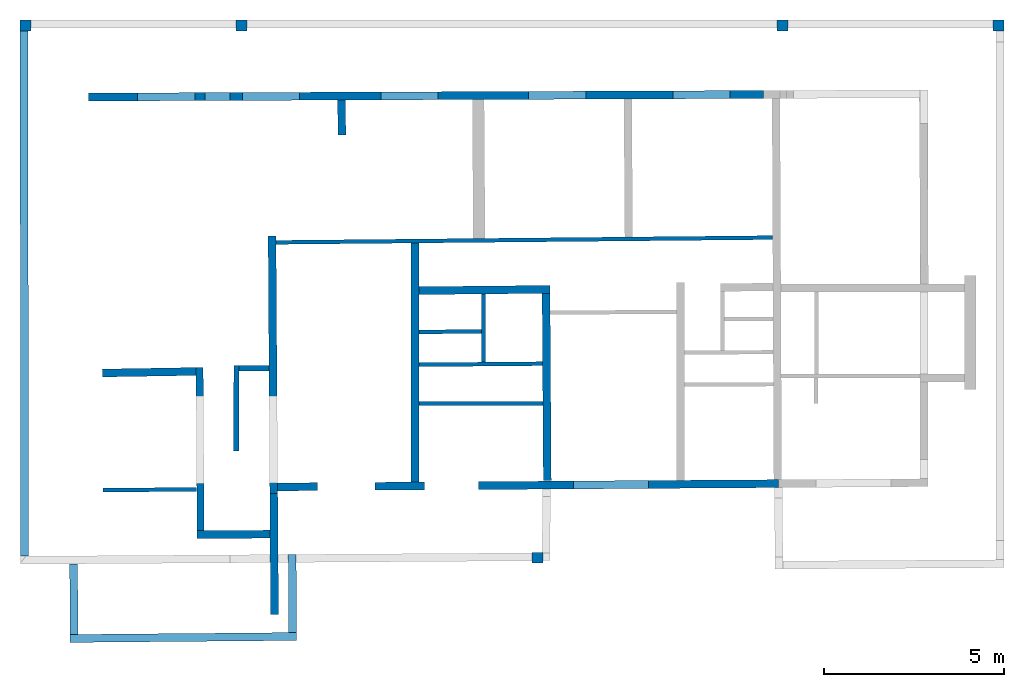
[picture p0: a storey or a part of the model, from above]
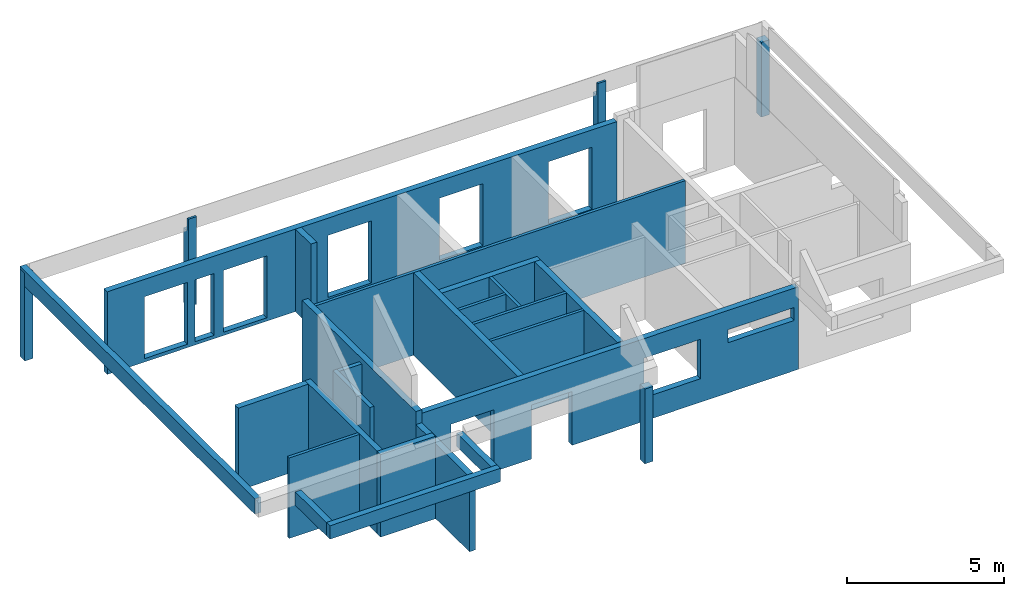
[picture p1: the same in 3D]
Properties of the parts of a building model (IFC2X3)

# File
Description: ViewDefinition [CoordinationView_V2.0], RevitIdentifiers [ContentGUID: feac69e5-6f6e-46f0-a33a-da2cc0dcfcfa, VersionGUID: e0802a1b-6d15-4124-863f-2c3c3ba81dfb, NumberOfSaves: 98], CoordinateReference [CoordinateBase: Origine interne, ProjectSite: Site par défaut]
File name: F3_26_978_MAQUETTE STRUCTURE_REFECTION TOITURE ONF_IFC IND 0_300926.ifc
Time: 2026-09-30T17:36:53+04:00
Author: Samuel Bello, s.bello@darwin-concept.fr
Organization: EICR
Written by: ODA SDAI 25.12
Made in: Autodesk Revit 26.2.0.20 (FRA) - IFC 26.2.0.20

# IfcProject, 09072019
LongName: SIDR_BAG; Phase: Etat du projet

# IfcSite, Default
RefLatitude: 42, 24, 53, 508911; RefLongitude: -71, -15, -29, -58837; RefElevation: 13090 cm

# IfcBuilding, e 39 logements et 22 maisons relais
LongName: e 39 logements et 22 maisons relais
Pset_BuildingCommon - NumberOfStoreys: 9

# IfcBuildingStorey: Niveau:Niveau NGR (3)
In: e 39 logements et 22 maisons relais
Name | LongName | Elevation (cm)
niv 0.00 | niv 0.00 | -13160
131.04 | 131.04 | 14
faîtage | faîtage | 825

# IfcBuildingStorey: Niveau:Niveau Relatif + NGR (6)
In: e 39 logements et 22 maisons relais
Name | LongName | Elevation (cm)
Fondations | Fondations | -410
Parking | Parking | -330
RDC | RDC | 0
R+1 | R+1 | 340
R+2 | R+2 | 610
R+3 | R+3 | 810

# IfcBeam: Poutre - Bois de construction de dimensions courantes:50 50 (239)
Type - PredefinedType: BEAM
Type - Pset_BeamCommon - LoadBearing: yes
Material: Bois - Bois de construction de dimensions courantes
Pset_BeamCommon - IsExternal: no; Reference: 50 50
Pset_QuantityTakeOff - Reference: 50 50; sets with these values: 2
Name (Poutre - Bois de construction de dimensions courantes:50 50:...) | In | Span (cm) | Slope (deg)
4829898 | R+2 | 364.7 | 19.8244
4829899 | R+2 | 364.7 | 36.3275
4829900 | R+2 | 364.7 | 36.933
4829901 | R+2 | 364.7 | 20.2495
4831531 | R+3 | 8.2 | 34.9359
4840642 | R+2 | 364.7 | 36.3605
4843238 | R+2 | 350.3 | 41.8622
4846561 | R+2 | 8.2 | 35.1202
4846562 | R+2 | 364.7 | 38.3386
4846563 | R+2 | 8.2 | 35.8385
4846564 | R+2 | 364.7 | 34.959
4851425 | R+2 | 350.3 | 41.9439
4883018 | R+2 | 364.7 | 19.8244 | Group: Groupe de modèles:Groupe 5:4883022
4883019 | R+2 | 364.7 | 36.3275 | Group: Groupe de modèles:Groupe 5:4883022
4883020 | R+2 | 364.7 | 36.933 | Group: Groupe de modèles:Groupe 5:4883022
4883021 | R+2 | 364.7 | 20.2495 | Group: Groupe de modèles:Groupe 5:4883022
4883032 | R+2 | 364.7 | 19.8244 | Group: Groupe de modèles:Groupe 5:4883036
4883033 | R+2 | 364.7 | 36.3275 | Group: Groupe de modèles:Groupe 5:4883036
4883034 | R+2 | 364.7 | 36.933 | Group: Groupe de modèles:Groupe 5:4883036
4883035 | R+2 | 364.7 | 20.2495 | Group: Groupe de modèles:Groupe 5:4883036
4883050 | R+2 | 364.7 | 19.8244 | Group: Groupe de modèles:Groupe 5:4883054
4883051 | R+2 | 364.7 | 36.3275 | Group: Groupe de modèles:Groupe 5:4883054
4883052 | R+2 | 364.7 | 36.933 | Group: Groupe de modèles:Groupe 5:4883054
4883053 | R+2 | 364.7 | 20.2495 | Group: Groupe de modèles:Groupe 5:4883054
4883089 | R+2 | 364.7 | 19.8244 | Group: Groupe de modèles:Groupe 5:4883093
4883090 | R+2 | 364.7 | 36.3275 | Group: Groupe de modèles:Groupe 5:4883093
4883091 | R+2 | 364.7 | 36.933 | Group: Groupe de modèles:Groupe 5:4883093
4883092 | R+2 | 364.7 | 20.2495 | Group: Groupe de modèles:Groupe 5:4883093
4883094 | R+2 | 364.7 | 19.8244 | Group: Groupe de modèles:Groupe 5:4883098
4883095 | R+2 | 364.7 | 36.3275 | Group: Groupe de modèles:Groupe 5:4883098
4883096 | R+2 | 364.7 | 36.933 | Group: Groupe de modèles:Groupe 5:4883098
4883097 | R+2 | 364.7 | 20.2495 | Group: Groupe de modèles:Groupe 5:4883098
4883099 | R+2 | 364.7 | 19.8244
4883100 | R+2 | 364.7 | 36.3275
4883101 | R+2 | 364.7 | 36.933
4883102 | R+2 | 364.7 | 20.2495
4883146 | R+2 | 364.7 | 19.6626
4883147 | R+2 | 364.7 | 36.6815
4883148 | R+2 | 364.7 | 36.382
4883149 | R+2 | 364.7 | 20.4762
4883202 | R+2 | 364.7 | 19.8244
4883203 | R+2 | 364.7 | 36.3275
4883204 | R+2 | 364.7 | 36.933
4883205 | R+2 | 364.7 | 20.2495
4883212 | R+2 | 364.7 | 19.8244
4883213 | R+2 | 364.7 | 36.3275
4883214 | R+2 | 364.7 | 36.933
4883215 | R+2 | 364.7 | 20.2495
4883217 | R+2 | 364.7 | 19.8244
4883218 | R+2 | 364.7 | 36.3275
4883219 | R+2 | 364.7 | 36.933
4883220 | R+2 | 364.7 | 20.2495
4883222 | R+2 | 364.7 | 19.8244
4883223 | R+2 | 364.7 | 36.3275
4883224 | R+2 | 364.7 | 36.933
4883225 | R+2 | 364.7 | 20.2495
4883239 | R+2 | 364.7 | 19.8244 | Group: Groupe de modèles:Groupe 5:4883243
4883240 | R+2 | 364.7 | 36.3275 | Group: Groupe de modèles:Groupe 5:4883243
4883241 | R+2 | 364.7 | 36.933 | Group: Groupe de modèles:Groupe 5:4883243
4883242 | R+2 | 364.7 | 20.2495 | Group: Groupe de modèles:Groupe 5:4883243
4883244 | R+2 | 364.7 | 19.8244 | Group: Groupe de modèles:Groupe 5:4883248
4883245 | R+2 | 364.7 | 36.3275 | Group: Groupe de modèles:Groupe 5:4883248
4883246 | R+2 | 364.7 | 36.933 | Group: Groupe de modèles:Groupe 5:4883248
4883247 | R+2 | 364.7 | 20.2495 | Group: Groupe de modèles:Groupe 5:4883248
4883249 | R+2 | 364.7 | 19.8244 | Group: Groupe de modèles:Groupe 5:4883253
4883250 | R+2 | 364.7 | 36.3275 | Group: Groupe de modèles:Groupe 5:4883253
4883251 | R+2 | 364.7 | 36.933 | Group: Groupe de modèles:Groupe 5:4883253
4883252 | R+2 | 364.7 | 20.2495 | Group: Groupe de modèles:Groupe 5:4883253
4883254 | R+2 | 364.7 | 19.8244 | Group: Groupe de modèles:Groupe 5:4883258
4883255 | R+2 | 364.7 | 36.3275 | Group: Groupe de modèles:Groupe 5:4883258
4883256 | R+2 | 364.7 | 36.933 | Group: Groupe de modèles:Groupe 5:4883258
4883257 | R+2 | 364.7 | 20.2495 | Group: Groupe de modèles:Groupe 5:4883258
4883259 | R+2 | 364.7 | 19.8244
4883260 | R+2 | 364.7 | 36.3275
4883261 | R+2 | 364.7 | 36.933
4883262 | R+2 | 364.7 | 20.2495
4883275 | R+2 | 364.7 | 19.8244 | Group: Groupe de modèles:Groupe 5:4883279
4883276 | R+2 | 364.7 | 36.3275 | Group: Groupe de modèles:Groupe 5:4883279
4883277 | R+2 | 364.7 | 36.933 | Group: Groupe de modèles:Groupe 5:4883279
4883278 | R+2 | 364.7 | 20.2495 | Group: Groupe de modèles:Groupe 5:4883279
4883280 | R+2 | 364.7 | 19.8244 | Group: Groupe de modèles:Groupe 5:4883284
4883281 | R+2 | 364.7 | 36.3275 | Group: Groupe de modèles:Groupe 5:4883284
4883282 | R+2 | 364.7 | 36.933 | Group: Groupe de modèles:Groupe 5:4883284
4883283 | R+2 | 364.7 | 20.2495 | Group: Groupe de modèles:Groupe 5:4883284
4883285 | R+2 | 364.7 | 19.8244 | Group: Groupe de modèles:Groupe 5:4883289
4883286 | R+2 | 364.7 | 36.3275 | Group: Groupe de modèles:Groupe 5:4883289
4883287 | R+2 | 364.7 | 36.933 | Group: Groupe de modèles:Groupe 5:4883289
4883288 | R+2 | 364.7 | 20.2495 | Group: Groupe de modèles:Groupe 5:4883289
4883290 | R+2 | 364.7 | 19.8244 | Group: Groupe de modèles:Groupe 5:4883294
4883291 | R+2 | 364.7 | 36.3275 | Group: Groupe de modèles:Groupe 5:4883294
4883292 | R+2 | 364.7 | 36.933 | Group: Groupe de modèles:Groupe 5:4883294
4883293 | R+2 | 364.7 | 20.2495 | Group: Groupe de modèles:Groupe 5:4883294
4883295 | R+2 | 364.7 | 19.8244 | Group: Groupe de modèles:Groupe 5:4883299
4883296 | R+2 | 364.7 | 36.3275 | Group: Groupe de modèles:Groupe 5:4883299
4883297 | R+2 | 364.7 | 36.933 | Group: Groupe de modèles:Groupe 5:4883299
4883298 | R+2 | 364.7 | 20.2495 | Group: Groupe de modèles:Groupe 5:4883299
4883331 | R+2 | 364.7 | 20.1552
4883332 | R+2 | 364.7 | 35.4788
4883333 | R+2 | 364.7 | 38.2563
4883334 | R+2 | 364.7 | 19.6937
4883336 | R+2 | 364.7 | 19.8244 | Group: Groupe de modèles:Groupe 5:4883340
4883337 | R+2 | 364.7 | 36.3275 | Group: Groupe de modèles:Groupe 5:4883340
4883338 | R+2 | 364.7 | 36.933 | Group: Groupe de modèles:Groupe 5:4883340
4883339 | R+2 | 364.7 | 20.2495 | Group: Groupe de modèles:Groupe 5:4883340
4883432 | R+2 | 364.7 | 19.8244
4883433 | R+2 | 364.7 | 36.3275
4883434 | R+2 | 364.7 | 36.933
4883435 | R+2 | 364.7 | 20.2495
4883478 | R+2 | 364.7 | 19.8244
4883479 | R+2 | 364.7 | 36.3275
4883480 | R+2 | 364.7 | 36.933
4883481 | R+2 | 364.7 | 20.2495
4883519 | R+2 | 364.7 | 19.8244
4883520 | R+2 | 364.7 | 36.3275
4883521 | R+2 | 364.7 | 36.933
4883522 | R+2 | 364.7 | 20.2495
4883581 | R+2 | 364.7 | 19.8244 | Group: Groupe de modèles:Groupe 5:4883585
4883582 | R+2 | 364.7 | 36.3275 | Group: Groupe de modèles:Groupe 5:4883585
4883583 | R+2 | 364.7 | 36.933 | Group: Groupe de modèles:Groupe 5:4883585
4883584 | R+2 | 364.7 | 20.2495 | Group: Groupe de modèles:Groupe 5:4883585
4901794 | R+2 | 364.7 | 35.9094
4907943 | R+3 | 8.2 | 34.9359
4907953 | R+3 | 8.2 | 34.9359
4907959 | R+3 | 8.2 | 34.9359
4907969 | R+3 | 8.2 | 34.9359
4908079 | R+3 | 8.2 | 34.9359
4908080 | R+3 | 8.2 | 35.9359
4908081 | R+3 | 8.2 | 34.9359
4908082 | R+3 | 8.2 | 34.9359
4908092 | R+3 | 8.2 | 34.9359
4908093 | R+3 | 8.2 | 34.9359
4908094 | R+3 | 8.2 | 34.9359
4908095 | R+3 | 8.2 | 34.9359
4908107 | R+3 | 8.2 | 35.9094
4915457 | R+2 | 364.7 | 35.9094
4915467 | R+2 | 364.7 | 35.9094
4915475 | R+2 | 364.7 | 35.9094
4915487 | R+2 | 364.7 | 35.9094
4915495 | R+2 | 364.7 | 35.9094
4915505 | R+2 | 364.7 | 35.9094
4915567 | R+2 | 364.7 | 35.9094
4916020 | R+2 | 8.2 | 35.4828
4916028 | R+2 | 8.2 | 35.4828
4916038 | R+2 | 8.2 | 35.4828
4916048 | R+2 | 8.2 | 35.4828
4916054 | R+2 | 8.2 | 35.4828
4916062 | R+2 | 8.2 | 35.4828
4916070 | R+2 | 8.2 | 35.4828
4916082 | R+2 | 8.2 | 35.4828
4932576 | R+2 | 8.2 | 35.4828
4932582 | R+2 | 8.2 | 35.4828
4932650 | R+2 | 8.2 | 35.4828
4932658 | R+2 | 8.2 | 35.4828
4932668 | R+2 | 8.2 | 35.4828
4932794 | R+2 | 8.2 | 35.4828
4932795 | R+2 | 8.2 | 35.4828
4932796 | R+2 | 8.2 | 35.4828
4932797 | R+2 | 8.2 | 35.4828
4932809 | R+2 | 8.2 | 35.4828
4932810 | R+2 | 8.2 | 35.4828
4932811 | R+2 | 8.2 | 35.4828
4932812 | R+2 | 8.2 | 35.4828
4932822 | R+2 | 8.2 | 35.4828
4932823 | R+2 | 8.2 | 35.4828
4932824 | R+2 | 8.2 | 35.4828
4932825 | R+2 | 8.2 | 35.4828
4932867 | R+2 | 8.2 | 35.4828
4932948 | R+2 | 8.2 | 35.4828
4932949 | R+2 | 8.2 | 35.4828
4932950 | R+2 | 8.2 | 35.4828
4932951 | R+2 | 8.2 | 35.4828
4932960 | R+2 | 8.2 | 35.4828
4932961 | R+2 | 8.2 | 35.4828
4932962 | R+2 | 8.2 | 35.4828
4946928 | R+2 | 350.3 | 41.8805
4946974 | R+2 | 350.3 | 41.8805
4947018 | R+2 | 350.3 | 41.8805
4947064 | R+2 | 350.3 | 41.8805
4947108 | R+2 | 350.3 | 41.8805
4947152 | R+2 | 350.3 | 41.8805
4947282 | R+2 | 350.3 | 41.8805
4947328 | R+2 | 350.3 | 41.8805
4947372 | R+2 | 350.3 | 41.8805
4947416 | R+2 | 350.3 | 41.8805
4948711 | R+2 | 350.3 | 41.9439
4949085 | R+2 | 350.3 | 41.9439
4949111 | R+2 | 350.3 | 41.9439
4949197 | R+2 | 350.3 | 41.8805
4949349 | R+2 | 350.3 | 41.8805
4949357 | R+2 | 350.3 | 41.8805
4949367 | R+2 | 350.3 | 41.8805
4949375 | R+2 | 350.3 | 41.8805
4949383 | R+2 | 350.3 | 41.8805
4949395 | R+2 | 350.3 | 41.8805
4949405 | R+2 | 350.3 | 41.8805
4949415 | R+2 | 350.3 | 41.8805
4949423 | R+2 | 350.3 | 41.8805
4951378 | R+2 | 8.2 | 35.1202
4951380 | R+2 | 8.2 | 35.8385
4951502 | R+2 | 8.2 | 35.1202
4951503 | R+2 | 8.2 | 35.8385
4951513 | R+2 | 8.2 | 35.1202
4951514 | R+2 | 8.2 | 35.8385
4951526 | R+2 | 8.2 | 35.1202
4951527 | R+2 | 8.2 | 35.8385
4951561 | R+2 | 8.2 | 35.1202
4951562 | R+2 | 8.2 | 35.8385
4952038 | R+2 | 8.2 | 35.8385
4952046 | R+2 | 8.2 | 35.8385
4952054 | R+2 | 8.2 | 35.8385
4960730 | R+2 | 350.3 | 41.8622
4960776 | R+2 | 350.3 | 41.8622
4960863 | R+2 | 350.3 | 41.8622
4960907 | R+2 | 350.3 | 41.8622
4960951 | R+2 | 350.3 | 41.8622
4960995 | R+2 | 350.3 | 41.8622
4961039 | R+2 | 350.3 | 41.8622
4961083 | R+2 | 350.3 | 41.8622
4961127 | R+2 | 350.3 | 41.8622
4961171 | R+2 | 350.3 | 41.8622
4961721 | R+2 | 350.3 | 41.8622
4961820 | R+2 | 350.3 | 41.8622
4961864 | R+2 | 350.3 | 41.8622
4961910 | R+2 | 350.3 | 41.8622
4961954 | R+2 | 350.3 | 41.8622
4961998 | R+2 | 350.3 | 41.8622
4962042 | R+2 | 350.3 | 41.8622
4962086 | R+2 | 350.3 | 41.8622
4962130 | R+2 | 350.3 | 41.8622
4962176 | R+2 | 350.3 | 41.8622
4962220 | R+2 | 350.3 | 41.8622
4970020 | R+2 | 8.2 | 35.4828
5042469 | R+2 | 8.2 | 35.1202
5042470 | R+2 | 364.7 | 38.3386
5042471 | R+2 | 8.2 | 35.8385
5042472 | R+2 | 364.7 | 34.959
5093514 | R+2 | 8.2 | 35.1202
5093524 | R+2 | 8.2 | 35.1202
5093532 | R+2 | 8.2 | 35.1202

# IfcBeam: Poutre - Bois de construction de dimensions courantes:70 100 (6)
Type - PredefinedType: BEAM
Type - Pset_BeamCommon - LoadBearing: yes
Material: Bois - Bois de construction de dimensions courantes
Pset_BeamCommon - IsExternal: no; Reference: 70 100
Pset_QuantityTakeOff - Reference: 70 100; sets with these values: 2
Name (Poutre - Bois de construction de dimensions courantes:70 100:...) | In | Span (cm) | Slope (deg)
4772331 | R+2 | 244.1 | 25.7882
4774475 | R+2 | 241.3 | 25.9653
4852667 | R+2 | 262.2 | 0
4853331 | R+3 | 262.2 | 0
4853339 | R+2 | 262.2 | 0
4853347 | R+2 | 262.2 | 0

# IfcBeam: Poutre - Bois de construction de dimensions courantes:70 200 (131)
Type - PredefinedType: BEAM
Type - Pset_BeamCommon - LoadBearing: yes
Material: Bois - Bois de construction de dimensions courantes
Pset_BeamCommon - IsExternal: no; Reference: 70 200
Pset_QuantityTakeOff - Reference: 70 200; sets with these values: 2
Name (Poutre - Bois de construction de dimensions courantes:70 200:...) | In | Span (cm) | Slope (deg)
4713617 | R+2 | 364.4 | 19.6829
4713659 | R+2 | 363.8 | 20.4762
4713696 | R+2 | 350.3 | 35.528
4713697 | R+2 | 364 | 35.7207
4713698 | R+1 | 221.5 | 0
4716714 | R+2 | 363.8 | 55.6387
4718998 | R+2 | 363.7 | 35.7207
4718999 | R+1 | 221.5 | 0
4720476 | faîtage | 221.5 | 0.151927
4720530 | faîtage | 221.5 | 0.0214582
4721840 | R+2 | 363.8 | 55.6387
4723570 | R+2 | 221.5 | 0
4724354 | R+2 | 221.5 | 0
4724410 | R+2 | 221.5 | 0
4724453 | R+2 | 221.5 | 0
4724504 | R+2 | 221.5 | 0
4724538 | R+3 | 221.5 | 0
4724595 | R+3 | 221.5 | 0
4725042 | R+3 | 221.5 | 0.201763
4725400 | faîtage | 221.5 | 0.141841
4725401 | faîtage | 221.5 | 0.0499903
4725402 | R+2 | 221.5 | 0
4725403 | R+2 | 221.5 | 0
4725404 | R+2 | 221.5 | 0
4725405 | R+2 | 221.5 | 0
4725406 | R+2 | 221.5 | 0
4725407 | R+3 | 221.5 | 0
4725408 | R+3 | 221.5 | 0
4725409 | R+3 | 221.5 | 0.239078
4727165 | R+1 | 221.5 | 0
4727559 | R+2 | 350.3 | 41.9619
4729826 | R+2 | 349.3 | 35.528
4730399 | R+2 | 364.4 | 20
4730420 | R+2 | 363.2 | 20.1834
4730442 | R+2 | 350.3 | 37.8496
4730443 | R+2 | 363.4 | 38
4730444 | R+2 | 221.5 | 0
4730466 | R+1 | 221.2 | 53.2663
4730481 | R+2 | 363.8 | 55.6387
4730534 | R+2 | 367.7 | 38
4730535 | R+2 | 221.5 | 0
4730550 | R+1 | 219.9 | 53.2663
4730619 | R+2 | 363.8 | 55.6387
4730755 | R+2 | 355.1 | 37.8496
4731622 | R+2 | 350.3 | 66.5157
4732101 | R+1 | 221.5 | 44
4732861 | R+1 | 221.5 | 0
4732862 | R+2 | 350.3 | 41.9619
4732876 | R+2 | 350.3 | 66.5157
4733129 | R+1 | 221.5 | 53
4733130 | R+1 | 221.5 | 0
4733131 | R+2 | 350.3 | 29.3869
4733145 | R+2 | 350.3 | 52.6147
4735480 | R+1 | 221.5 | 0
4735481 | R+2 | 351.2 | 29.3869
4735495 | R+2 | 350.3 | 52.6147
4735910 | R+2 | 350.3 | 41.9619
4737384 | R+2 | 350.3 | 41.9619
4738993 | R+2 | 113.9 | 29.3869
4739526 | R+2 | 113.9 | 29.3869
4739680 | R+2 | 113.9 | 29.3869
4739693 | R+2 | 113.9 | 29.3869
4744478 | R+1 | 221.5 | 0.0305164
4744486 | R+1 | 221.5 | 0.0283479
4744536 | R+1 | 221.5 | 0.0105581
4744757 | R+2 | 221.5 | 30.4756
4745406 | R+2 | 221.5 | 30.4756
4745808 | R+1 | 110.1 | 0.185532
4746326 | R+1 | 202.2 | 0
4746422 | R+1 | 214.2 | 0.359982
4746951 | R+2 | 113.4 | 35.1814
4750679 | R+1 | 221.5 | 53
4750680 | R+1 | 221.5 | 0
4750681 | R+2 | 350.3 | 29.3869
4750695 | R+2 | 354.9 | 51.6489
4750729 | R+1 | 221.5 | 0
4750730 | R+2 | 351.2 | 29.3869
4750744 | R+2 | 350.3 | 52.6147
4754543 | faîtage | 221.5 | 0
4754544 | R+2 | 221.5 | 0
4754545 | R+2 | 221.5 | 0
4754546 | R+2 | 221.5 | 0
4754547 | R+3 | 221.5 | 0
4754548 | R+3 | 221.5 | 0
4754549 | R+2 | 221.5 | 0
4754550 | R+1 | 221.5 | 0
4754551 | R+1 | 221.5 | 0
4754552 | R+1 | 221.5 | 0
4756969 | R+1 | 221.5 | 53
4756970 | R+1 | 221.5 | 0
4756971 | R+2 | 350.3 | 29.3869
4756985 | R+2 | 354.9 | 51.6489
4757006 | R+1 | 221.5 | 0
4757007 | R+2 | 351.2 | 29.3869
4757021 | R+2 | 350.3 | 52.6147
4757707 | R+1 | 221.5 | 0
4757708 | R+2 | 350.3 | 41.8805
4757722 | R+2 | 350.3 | 71.3198
4757723 | R+1 | 185.2 | 30.6789
4757787 | R+1 | 221.5 | 0
4757788 | R+2 | 350.3 | 41.8805
4757802 | R+2 | 350.3 | 71.3198
4758155 | R+1 | 221.5 | 0
4758156 | R+2 | 350.3 | 29.3869
4758170 | R+2 | 354.9 | 51.6489
4758184 | R+1 | 221.5 | 0
4758185 | R+2 | 351.2 | 29.3869
4759985 | R+2 | 363.8 | 20.3198
4760008 | R+2 | 221.5 | 0
4760055 | R+2 | 363.7 | 35.9222
4760056 | R+2 | 221.5 | 0
4771403 | R+2 | 330.7 | 52.6147
4814569 | R+3 | 221.5 | 0.173631
4814640 | R+2 | 221.5 | 0.044149
4814849 | R+3 | 221.5 | 0.149923
4814945 | R+3 | 221.5 | 0.113566
4814953 | R+2 | 221.5 | 0.0922914
4814961 | R+2 | 221.5 | 0.071892
4817865 | R+2 | 221.5 | 0.056568
4818210 | R+3 | 221.5 | 0.265412
4818318 | R+3 | 221.5 | 0.22199
4818326 | R+3 | 221.5 | 0.195658
4818334 | R+2 | 221.5 | 0.140445
4818342 | R+2 | 221.5 | 0.107412
4822862 | R+2 | 221.5 | 0
4825191 | R+1 | 221.5 | 0
4861459 | R+1 | 110.1 | 0
4908987 | R+1 | 8.2 | 35.9359
4959918 | R+1 | 221.5 | 0
5052351 | R+1 | 221.5 | 0
5077321 | R+2 | 221.5 | 0

# IfcBeam: Poutre - Bois de construction de dimensions courantes:70 220 (62)
Type - PredefinedType: BEAM
Type - Pset_BeamCommon - LoadBearing: yes
Material: Bois - Bois de construction de dimensions courantes
Pset_BeamCommon - IsExternal: no; Reference: 70 220
Pset_QuantityTakeOff - Reference: 70 220; sets with these values: 2
Name (Poutre - Bois de construction de dimensions courantes:70 220:...) | In | Span (cm) | Slope (deg)
4713592 | R+1 | 237.6 | 14.6236
4713594 | R+3 | 221.5 | 90
4713595 | R+2 | 221.5 | 48.2899
4713673 | R+2 | 221.5 | 48.2899
4730397 | R+3 | 221.5 | 90
4730398 | R+3 | 221.5 | 48.2899
4730434 | R+2 | 221.5 | 48.2899
4734657 | faîtage | 221.5 | 0
4735640 | faîtage | 221.5 | 0
4735753 | R+2 | 221.5 | 0
4735830 | R+2 | 221.5 | 0
4735840 | R+2 | 221.5 | 0
4735848 | R+3 | 221.5 | 0
4735858 | R+3 | 221.5 | 0
4738468 | R+2 | 221.5 | 0
4738478 | R+1 | 221.5 | 0
4738536 | R+1 | 221.5 | 0
4738544 | R+1 | 221.5 | 0
4756946 | R+2 | 221.5 | 0
4756947 | R+2 | 221.5 | 0
4756948 | R+2 | 221.5 | 0
4756949 | R+2 | 221.5 | 0
4756950 | R+2 | 221.5 | 0
4756951 | R+3 | 221.5 | 0
4756966 | R+1 | 110.1 | 0.00164146
4756967 | R+1 | 202.2 | 0.00000561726
4756968 | R+1 | 214.2 | 0.00124997
4758423 | R+2 | 221.5 | 0
4758424 | R+2 | 221.5 | 0
4758425 | R+2 | 221.5 | 0
4758426 | R+2 | 221.5 | 0
4758427 | R+2 | 221.5 | 0
4758428 | R+3 | 221.5 | 0
4758429 | R+3 | 221.5 | 0
4759984 | R+3 | 221.5 | 90
4759999 | R+2 | 221.5 | 48.2899
4761052 | R+2 | 221.5 | 48.2899
4761130 | R+2 | 221.5 | 48.2899
4781361 | R+3 | 221.5 | 90
4781525 | R+3 | 221.5 | 90
4781787 | R+3 | 221.5 | 90
4823297 | R+2 | 221.5 | 34.3613
4823676 | R+2 | 221.5 | 36.7337
4847030 | R+3 | 221.5 | 0
4859424 | R+2 | 221.5 | 0
4859725 | R+1 | 221.5 | 0
4859802 | R+1 | 221.5 | 0
4861302 | R+1 | 221.5 | 0
4861373 | R+1 | 221.5 | 0
4863640 | R+1 | 221.5 | 0.0480418
4871452 | R+1 | 221.5 | 0
4907774 | R+1 | 8.2 | 34.9359
4914506 | R+1 | 202.2 | 0
4914626 | R+1 | 202.2 | 0
4930961 | R+1 | 8.5 | 35.4828
4932316 | R+1 | 8.5 | 35.4828
4932326 | R+1 | 8.5 | 35.4828
4932402 | R+1 | 8.5 | 35.4828
4933417 | R+1 | 221.5 | 0.00000792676
5058196 | R+1 | 202.2 | 0
5058197 | R+1 | 202.2 | 0
5069516 | R+1 | 214.2 | 0.00124997

# IfcBeam: Poutre - Bois de construction de dimensions courantes:70 70 (2)
In: R+2
Type - PredefinedType: BEAM
Type - Pset_BeamCommon - LoadBearing: yes
Material: Bois - Bois de construction de dimensions courantes
Pset_BeamCommon - IsExternal: no; Slope: 90 deg; Reference: 70 70; Span: 254.6 cm
Pset_QuantityTakeOff - Reference: 70 70; sets with these values: 2
Name (Poutre - Bois de construction de dimensions courantes:70 70:...)
4774043
4774476

# IfcBeam: SHS (EN 10210-2):SHS60x5, SHS (EN 10210-2):SHS60x5:5058198
In: R+1
Type - PredefinedType: BEAM
Type - Pset_BeamCommon - LoadBearing: yes
Material: Acier structurel - S235
Pset_BeamCommon - IsExternal: no; Slope: 0 deg; Reference: SHS60x5; Span: 202.22 cm
Pset_QuantityTakeOff - Reference: SHS60x5; sets with these values: 2

# IfcBeam: gouttiere ALU G400:gouttiere ALU G400 (9)
Type - PredefinedType: BEAM
Type - Pset_BeamCommon - LoadBearing: yes
Material: neuf
Pset_BeamCommon - IsExternal: no; Slope: 0 deg; Span: 221.5 cm; Reference: gouttiere ALU G400
Pset_QuantityTakeOff - Reference: gouttiere ALU G400; sets with these values: 2
Name (gouttiere ALU G400:gouttiere ALU G400:...) | In
4725530 | R+2
4743490 | R+1
4743888 | R+1
4743925 | R+1
4752707 | R+1
4768051 | R+1
5048577 | R+2
5050955 | R+1
5089896 | R+2

# IfcBeam: panne z inv:panne z inv, panne z inv:panne z inv:5026788
In: R+2
Type - PredefinedType: BEAM
Type - Pset_BeamCommon - LoadBearing: yes
Material: neuf
Pset_BeamCommon - IsExternal: no; Slope: 0 deg; Span: 221.5 cm; Reference: panne z inv
Pset_QuantityTakeOff - Reference: panne z inv; sets with these values: 2

# IfcBeam: panne z pente sup 20 deg:panne z pente sup 20 deg (2)
In: R+2
Type - PredefinedType: BEAM
Type - Pset_BeamCommon - LoadBearing: yes
Material: neuf
Pset_BeamCommon - IsExternal: no; Span: 221.5 cm; Reference: panne z pente sup 20 deg
Pset_QuantityTakeOff - Reference: panne z pente sup 20 deg; sets with these values: 2
Name (panne z pente sup 20 deg:panne z pente sup 20 deg:...) | Slope (deg)
4920119 | 0
5077280 | 0.0192804

# IfcBeam: panne z pente sup 35 deg 4:panne z pente sup 35 deg 4 (2)
In: R+1
Type - PredefinedType: BEAM
Type - Pset_BeamCommon - LoadBearing: yes
Material: neuf
Pset_BeamCommon - IsExternal: no; Reference: panne z pente sup 35 deg 4; Span: 221.5 cm
Pset_QuantityTakeOff - Reference: panne z pente sup 35 deg 4; sets with these values: 2
Name (panne z pente sup 35 deg 4:panne z pente sup 35 deg 4:...) | Slope (deg)
4921457 | 0.0958997
4937450 | 0

# IfcBeam: panne z pente sup 35 deg2:panne z pente sup 35 deg2 (2)
In: R+1
Type - PredefinedType: BEAM
Type - Pset_BeamCommon - LoadBearing: yes
Material: neuf
Pset_BeamCommon - IsExternal: no; Slope: 0 deg; Span: 221.5 cm; Reference: panne z pente sup 35 deg2
Pset_QuantityTakeOff - Reference: panne z pente sup 35 deg2; sets with these values: 2
Name (panne z pente sup 35 deg2:panne z pente sup 35 deg2:...)
4972562
5050316

# IfcBeam: panne z pente sup 42 deg4:panne z pente sup 42 deg4, panne z pente sup 42 deg4:panne z pente sup 42 deg4:4939766
In: R+1
Type - PredefinedType: BEAM
Type - Pset_BeamCommon - LoadBearing: yes
Material: neuf
Pset_BeamCommon - IsExternal: no; Slope: 0 deg; Span: 221.5 cm; Reference: panne z pente sup 42 deg4
Pset_QuantityTakeOff - Reference: panne z pente sup 42 deg4; sets with these values: 2

# IfcBeam: panne z pente sup 42 deg:panne z pente sup 42 deg, panne z pente sup 42 deg:panne z pente sup 42 deg:4871357
In: R+1
Type - PredefinedType: BEAM
Type - Pset_BeamCommon - LoadBearing: yes
Material: neuf
Pset_BeamCommon - IsExternal: no; Slope: 0 deg; Span: 221.5 cm; Reference: panne z pente sup 42 deg
Pset_QuantityTakeOff - Reference: panne z pente sup 42 deg; sets with these values: 2

# IfcBeam: panne z:panne z (91)
Type - PredefinedType: BEAM
Type - Pset_BeamCommon - LoadBearing: yes
Material: neuf
Pset_BeamCommon - IsExternal: no; Reference: panne z
Pset_QuantityTakeOff - Reference: panne z; sets with these values: 2
Name (panne z:panne z:...) | In | Span (cm) | Slope (deg)
4811214 | faîtage | 221.501 | 0.129336
4811614 | R+1 | 221.5 | 0.0445631
4811864 | R+1 | 221.5 | 0.0582049
4811989 | R+1 | 221.5 | 0.0310049
4814641 | R+2 | 221.5 | 0.0428046
4815225 | R+2 | 221.5 | 0.0576339
4815236 | R+3 | 221.5 | 0.0612113
4815247 | R+3 | 221.5 | 0.0776015
4815260 | R+3 | 221.501 | 0.144793
4817261 | faîtage | 221.5 | 0.0333975
4820741 | R+3 | 221.501 | 0.155203
4820853 | R+2 | 221.5 | 0.0284703
4822356 | faîtage | 221.5 | 0.0517343
4824144 | faîtage | 221.501 | 0.145883
4824261 | R+3 | 221.502 | 0.226364
4824339 | R+3 | 221.502 | 0.25867
4824416 | R+3 | 221.502 | 0.232803
4824428 | R+3 | 221.501 | 0.181467
4824436 | R+3 | 221.501 | 0.142083
4824503 | R+2 | 221.5 | 0.10609
4824568 | R+2 | 221.5 | 0.0727537
4824642 | R+2 | 221.5 | 0.0298794
4832383 | R+1 | 221.5 | 0
4833474 | R+2 | 221.5 | 0
4835512 | R+2 | 221.5 | 0
4835523 | R+2 | 221.5 | 0
4835532 | R+2 | 221.5 | 0
4835540 | R+3 | 221.5 | 0
4835994 | R+3 | 221.5 | 0
4836714 | R+2 | 221.5 | 0
4838885 | R+1 | 221.5 | 0
4839220 | R+1 | 221.501 | 0.129336
4839550 | R+1 | 221.503 | 0.284537
4840247 | R+2 | 221.5 | 0
4840248 | R+2 | 221.5 | 0
4840249 | R+2 | 221.5 | 0
4840250 | R+2 | 221.5 | 0
4840251 | R+3 | 221.5 | 0
4840252 | R+3 | 221.5 | 0
4840253 | R+2 | 221.5 | 0
4841879 | R+2 | 221.5 | 0
4842399 | R+3 | 221.501 | 0.19869
4843854 | R+1 | 221.5 | 0
4843952 | R+1 | 221.5 | 0
4843960 | R+1 | 221.5 | 0
4843968 | R+2 | 221.5 | 0
4843978 | R+2 | 221.5 | 0
4843986 | R+2 | 221.5 | 0
4843996 | R+2 | 221.5 | 0
4844006 | R+3 | 221.5 | 0
4844014 | R+3 | 221.5 | 0
4844022 | R+3 | 221.5 | 0
4844030 | faîtage | 221.5 | 0
4846025 | R+1 | 221.5 | 0
4846026 | R+1 | 221.5 | 0
4846027 | R+1 | 221.5 | 0
4846028 | R+2 | 221.5 | 0
4846029 | R+2 | 221.5 | 0
4846030 | R+2 | 221.5 | 0
4846031 | R+2 | 221.5 | 0
4846032 | R+3 | 221.5 | 0
4846033 | R+3 | 221.5 | 0
4846034 | R+3 | 221.5 | 0
4846035 | faîtage | 221.5 | 0
4846135 | R+2 | 221.5 | 0
4846136 | R+2 | 221.5 | 0
4846137 | R+2 | 221.5 | 0
4846138 | R+2 | 221.5 | 0
4846139 | R+3 | 221.5 | 0
4846142 | R+1 | 221.5 | 0
4846143 | R+2 | 221.5 | 0
4846144 | R+2 | 221.5 | 0
4846145 | R+2 | 221.5 | 0
4846146 | R+2 | 221.5 | 0
4846147 | R+3 | 221.5 | 0
4846148 | R+3 | 221.5 | 0
4846149 | R+2 | 221.5 | 0
4846150 | R+2 | 221.505 | 0.398255
4848237 | R+3 | 221.5 | 0
4848455 | R+1 | 221.5 | 0
4848688 | R+1 | 221.5 | 0
4852106 | R+2 | 221.5 | 0
4936173 | R+2 | 221.5 | 0
4936183 | R+2 | 221.5 | 0
4943531 | R+2 | 221.5 | 0
4943699 | R+2 | 221.5 | 0
4943953 | R+2 | 221.5 | 0
4973361 | faîtage | 221.5 | 0.0333975
4973394 | faîtage | 221.5 | 0.0517343
5023602 | R+2 | 221.5 | 0
5041909 | R+2 | 221.5 | 0

# IfcBeam: tpg appui de baie2:tpg appui de baie2, tpg appui de baie2:tpg appui de baie2:4955302
In: R+2
Type - PredefinedType: BEAM
Type - Pset_BeamCommon - LoadBearing: yes
Material: neuf
Pset_BeamCommon - IsExternal: no; Slope: 0 deg; Reference: tpg appui de baie2; Span: 1999.9 cm
Pset_QuantityTakeOff - Reference: tpg appui de baie2; sets with these values: 2

# IfcBeam: tpg appui de baie:tpg appui de baie (2)
In: R+2
Type - PredefinedType: BEAM
Type - Pset_BeamCommon - LoadBearing: yes
Material: neuf
Pset_BeamCommon - IsExternal: no; Slope: 0 deg; Reference: tpg appui de baie; Span: 230.668 cm
Pset_QuantityTakeOff - Reference: tpg appui de baie; sets with these values: 2
Name (tpg appui de baie:tpg appui de baie:...)
4952337
4955019

# IfcBuildingElementProxy: Ossature 1:Ossature 1, Ossature 1:Ossature 1:5033211
In: R+1
Type - Material: tole
Pset_BuildingElementProxyCommon - Reference: Ossature 1; sets with these values: 2

# IfcBuildingElementProxy: Ossature 2:Ossature 2, Ossature 2:Ossature 2:4972002
In: R+1
Type - Material: tole
Pset_BuildingElementProxyCommon - Reference: Ossature 2; sets with these values: 2

# IfcColumn: Poteau béton - Rectangulaire:30x30 (5)
In: RDC
Type - PredefinedType: COLUMN; Material: Maçonnerie - Béton coulé sur place
Type - Pset_ColumnCommon - LoadBearing: yes
Pset_ColumnCommon - Reference: 30x30; IsExternal: no
Pset_QuantityTakeOff - Reference: 30x30; sets with these values: 2
Name (Poteau béton - Rectangulaire:30x30:...)
4683313
4683376
4683419 | Pset_ColumnCommon - Slope: 0 deg
4683471 | Pset_ColumnCommon - Slope: 0 deg
4683516

# IfcDistributionPort (126)
Description: Flow; FlowDirection: SOURCEANDSINK
Name | Group
Port_5036833_0 | Alimentation hydraulique 1
Port_5054493_1 | Alimentation hydraulique 1
Port_5036833_1 | Alimentation hydraulique 1
Port_5037067_0 | Alimentation hydraulique 2
Port_5059496_1 | Alimentation hydraulique 2
Port_5037067_1 | Alimentation hydraulique 2
Port_5037369_0 | Alimentation hydraulique 3
Port_5059446_1 | Alimentation hydraulique 3
Port_5037369_1 | Alimentation hydraulique 3
Port_5037414_0 | Alimentation hydraulique 4
Port_5038021_1 | Alimentation hydraulique 4
Port_5037414_1 | Alimentation hydraulique 4
Port_5038010_0 | Alimentation hydraulique 4
Port_5038021_2 | Alimentation hydraulique 4
Port_5038010_1 | Alimentation hydraulique 4
Port_5038029_1 | Alimentation hydraulique 4
Port_5038023_0 | Alimentation hydraulique 4
Port_5038029_2 | Alimentation hydraulique 4
Port_5038023_1 | Alimentation hydraulique 4
Port_5038396_0 | Alimentation hydraulique 6
Port_5038939_1 | Alimentation hydraulique 6
Port_5038396_1 | Alimentation hydraulique 6
Port_5038826_0 | Alimentation hydraulique 6
Port_5038939_2 | Alimentation hydraulique 6
Port_5038826_1 | Alimentation hydraulique 6
Port_5038956_1 | Alimentation hydraulique 6
Port_5038948_0 | Alimentation hydraulique 6
Port_5038956_2 | Alimentation hydraulique 6
Port_5038948_1 | Alimentation hydraulique 6
Port_5039902_0 | Alimentation hydraulique 5
Port_5039943_1 | Alimentation hydraulique 5
Port_5039902_1 | Alimentation hydraulique 5
Port_5039911_0 | Alimentation hydraulique 5
Port_5039943_2 | Alimentation hydraulique 5
Port_5039911_1 | Alimentation hydraulique 5
Port_5039945_1 | Alimentation hydraulique 5
Port_5039920_0 | Alimentation hydraulique 5
Port_5039945_2 | Alimentation hydraulique 5
Port_5039920_1 | Alimentation hydraulique 5
Port_5040652_0 | Alimentation hydraulique 7
Port_5041097_1 | Alimentation hydraulique 7
Port_5040652_1 | Alimentation hydraulique 7
Port_5041086_0 | Alimentation hydraulique 7
Port_5041097_2 | Alimentation hydraulique 7
Port_5041086_1 | Alimentation hydraulique 7
Port_5041105_1 | Alimentation hydraulique 7
Port_5041099_0 | Alimentation hydraulique 7
Port_5041105_2 | Alimentation hydraulique 7
Port_5041099_1 | Alimentation hydraulique 7
Port_5041165_0 | Alimentation hydraulique 8
Port_5041169_1 | Alimentation hydraulique 8
Port_5041165_1 | Alimentation hydraulique 8
Port_5041167_0 | Alimentation hydraulique 8
Port_5041169_2 | Alimentation hydraulique 8
Port_5041167_1 | Alimentation hydraulique 8
Port_5041173_1 | Alimentation hydraulique 8
Port_5041171_0 | Alimentation hydraulique 8
Port_5041173_2 | Alimentation hydraulique 8
Port_5041171_1 | Alimentation hydraulique 8
Port_5041327_0 | Alimentation hydraulique 9
Port_5041327_1 | Alimentation hydraulique 9
Port_5041331_1 | Alimentation hydraulique 9
Port_5041329_0 | Alimentation hydraulique 9
Port_5041331_2 | Alimentation hydraulique 9
Port_5041329_1 | Alimentation hydraulique 9
Port_5041335_1 | Alimentation hydraulique 9
Port_5041333_0 | Alimentation hydraulique 9
Port_5041335_2 | Alimentation hydraulique 9
Port_5041333_1 | Alimentation hydraulique 9
Port_5041536_0 | Alimentation hydraulique 10
Port_5041540_1 | Alimentation hydraulique 10
Port_5041536_1 | Alimentation hydraulique 10
Port_5041538_0 | Alimentation hydraulique 10
Port_5041540_2 | Alimentation hydraulique 10
Port_5041538_1 | Alimentation hydraulique 10
Port_5041544_1 | Alimentation hydraulique 10
Port_5041542_0 | Alimentation hydraulique 10
Port_5041544_2 | Alimentation hydraulique 10
Port_5041542_1 | Alimentation hydraulique 10
Port_5044864_0 | Alimentation hydraulique 15
Port_5044864_1 | Alimentation hydraulique 15
Port_5045765_1 | Alimentation hydraulique 15
Port_5044962_0 | Alimentation hydraulique 12
Port_5044964_1 | Alimentation hydraulique 12
Port_5044962_1 | Alimentation hydraulique 12
Port_5044964_2 | Alimentation hydraulique 12
Port_5045108_0 | Alimentation hydraulique 13
Port_5045934_1 | Alimentation hydraulique 13
Port_5045108_1 | Alimentation hydraulique 13
Port_5045113_0 | Alimentation hydraulique 14
Port_5045115_1 | Alimentation hydraulique 14
Port_5045113_1 | Alimentation hydraulique 14
Port_5045115_2 | Alimentation hydraulique 14
Port_5045435_0 | Alimentation hydraulique 11
Port_5045560_1 | Alimentation hydraulique 11
Port_5045435_1 | Alimentation hydraulique 11
Port_5045560_2 | Alimentation hydraulique 11
Port_5045755_0 | Alimentation hydraulique 15
Port_5045765_2 | Alimentation hydraulique 15
Port_5045755_1 | Alimentation hydraulique 15
Port_5045926_0 | Alimentation hydraulique 13
Port_5045934_2 | Alimentation hydraulique 13
Port_5045926_1 | Alimentation hydraulique 13
Port_5049302_0 | Alimentation hydraulique 16
Port_5049302_1 | Alimentation hydraulique 16
Port_5054482_0 | Alimentation hydraulique 1
Port_5054493_2 | Alimentation hydraulique 1
Port_5054482_1 | Alimentation hydraulique 1
Port_5054504_1 | Alimentation hydraulique 1
Port_5054495_0 | Alimentation hydraulique 1
Port_5054504_2 | Alimentation hydraulique 1
Port_5054495_1 | Alimentation hydraulique 1
Port_5059435_0 | Alimentation hydraulique 3
Port_5059446_2 | Alimentation hydraulique 3
Port_5059435_1 | Alimentation hydraulique 3
Port_5059454_1 | Alimentation hydraulique 3
Port_5059448_0 | Alimentation hydraulique 3
Port_5059454_2 | Alimentation hydraulique 3
Port_5059448_1 | Alimentation hydraulique 3
Port_5059485_0 | Alimentation hydraulique 2
Port_5059496_2 | Alimentation hydraulique 2
Port_5059485_1 | Alimentation hydraulique 2
Port_5059504_1 | Alimentation hydraulique 2
Port_5059498_0 | Alimentation hydraulique 2
Port_5059504_2 | Alimentation hydraulique 2
Port_5059498_1 | Alimentation hydraulique 2

# IfcFlowFitting: Coude - PVC - Nom. 40:Standard (25)
In: R+1
Type - Material: <Unnamed>
Pset_DistributionFlowElementCommon - Reference: Standard; sets with these values: 2
Name (Coude - PVC - Nom. 40:Standard:...) | Group
5038021 | Alimentation hydraulique 4
5038029 | Alimentation hydraulique 4
5038939 | Alimentation hydraulique 6
5038956 | Alimentation hydraulique 6
5039943 | Alimentation hydraulique 5
5039945 | Alimentation hydraulique 5
5041097 | Alimentation hydraulique 7
5041105 | Alimentation hydraulique 7
5041169 | Alimentation hydraulique 8
5041173 | Alimentation hydraulique 8
5041331 | Alimentation hydraulique 9
5041335 | Alimentation hydraulique 9
5041540 | Alimentation hydraulique 10
5041544 | Alimentation hydraulique 10
5044964 | Alimentation hydraulique 12
5045115 | Alimentation hydraulique 14
5045560 | Alimentation hydraulique 11
5045765 | Alimentation hydraulique 15
5045934 | Alimentation hydraulique 13
5054493 | Alimentation hydraulique 1
5054504 | Alimentation hydraulique 1
5059446 | Alimentation hydraulique 3
5059454 | Alimentation hydraulique 3
5059496 | Alimentation hydraulique 2
5059504 | Alimentation hydraulique 2

# IfcFlowSegment: Canalisation:Par défaut (38)
In: R+1
Pset_DistributionFlowElementCommon - Reference: Par défaut; sets with these values: 2
Pset_FlowSegmentDuctSegment - sets with these values: 2
Name (Canalisation:Par défaut:...) | Length (cm) | Group
5036833 | 265.284 | Alimentation hydraulique 1
5037067 | 253.184 | Alimentation hydraulique 2
5037369 | 263.584 | Alimentation hydraulique 3
5037414 | 268.288 | Alimentation hydraulique 4
5038010 | 11.775 | Alimentation hydraulique 4
5038023 | 17.0875 | Alimentation hydraulique 4
5038396 | 33.2806 | Alimentation hydraulique 6
5038826 | 199.887 | Alimentation hydraulique 6
5038948 | 266.426 | Alimentation hydraulique 6
5039902 | 37.7579 | Alimentation hydraulique 5
5039911 | 188.668 | Alimentation hydraulique 5
5039920 | 251.719 | Alimentation hydraulique 5
5040652 | 12.2875 | Alimentation hydraulique 7
5041086 | 17.5196 | Alimentation hydraulique 7
5041099 | 73.0842 | Alimentation hydraulique 7
5041165 | 15.6218 | Alimentation hydraulique 8
5041167 | 5.66011 | Alimentation hydraulique 8
5041171 | 73.0842 | Alimentation hydraulique 8
5041327 | 8.76495 | Alimentation hydraulique 9
5041329 | 23.6631 | Alimentation hydraulique 9
5041333 | 73.0842 | Alimentation hydraulique 9
5041536 | 10.5875 | Alimentation hydraulique 10
5041538 | 16.9048 | Alimentation hydraulique 10
5041542 | 73.0842 | Alimentation hydraulique 10
5044864 | 192.63 | Alimentation hydraulique 15
5044962 | 41.2 | Alimentation hydraulique 12
5045108 | 205.358 | Alimentation hydraulique 13
5045113 | 26.5 | Alimentation hydraulique 14
5045435 | 16.8875 | Alimentation hydraulique 11
5045755 | 11.9932 | Alimentation hydraulique 15
5045926 | 267.483 | Alimentation hydraulique 13
5049302 | 38.5 | Alimentation hydraulique 16
5054482 | 18.7675 | Alimentation hydraulique 1
5054495 | 10.2838 | Alimentation hydraulique 1
5059435 | 15.6675 | Alimentation hydraulique 3
5059448 | 15.6838 | Alimentation hydraulique 3
5059485 | 37.6821 | Alimentation hydraulique 2
5059498 | 12.2838 | Alimentation hydraulique 2

# IfcOpeningElement: Opening (25)
Name (Mur de base:...) | In
2 x BA - 22cm:4677164 | 131.04 | Pset_OpeningElementCommon - Reference: 195 150; sets with these values: 2
2 x BA - 22cm:4751273 | 131.04 | Pset_OpeningElementCommon - Reference: 195 150; sets with these values: 2
4 x BA - 22cm:4678810 | RDC
BA - 22cm:4679911 | RDC
BA - 22cm:4680275 | RDC
BA - 22cm:4684822 | R+1
BA - 18cm:4687341 | R+1
2 x cloison 11cm:4687512 | R+1
cloison 11cm:4688067 | R+1
BA - 22cm:4765226 | R+1
6 x BA - 22cm:4799169 | RDC
2 x BA - 22cm:4799284 | RDC
BA - 22cm:5052657 | 131.04

# IfcRoof: Toit de base:Tôle 1000P (14)
Material: tole 4 cm
Pset_QuantityTakeOff - Reference: Tôle 1000P
Pset_RoofCommon - IsExternal: yes; Reference: Tôle 1000P
Name (Toit de base:Tôle 1000P:...) | In | ProjectedArea (m2) | TotalArea (m2)
4809144 | faîtage | 71.3887 | 75.9124
4824014 | faîtage | 73.3407 | 78.0481
4832655 | faîtage | 21.0689 | 26.5697
4832814 | R+3 | 22.2631 | 27.4648
4839895 | R+2 | 15.2618 | 18.8807
4842617 | faîtage | 48.8104 | 65.6415
4846007 | R+3 | 24.9597 | 30.485
4846017 | faîtage | 49.4084 | 63.0819
4865372 | faîtage | 24.6208 | 30.3497
4865383 | R+3 | 22.2327 | 27.3186
4876019 | R+2 | 25.8924 | 31.9693
4876051 | R+3 | 24.336 | 30.0845
4936204 | faîtage | 2.51465 | 2.79131
4963625 | R+1 | 0.607576 | 0.741404

# IfcSlab: Sol:Dalle BA - 20 (5)
Type - PredefinedType: FLOOR; Material: Béton - Béton coulé sur place 20 cm
Pset_QuantityTakeOff - Reference: Dalle BA - 20; sets with these values: 2
Pset_SlabCommon - LoadBearing: yes; IsExternal: no; Reference: Dalle BA - 20; PitchAngle: 0 deg
Name (Sol:Dalle BA - 20:...) | In
4688603 | R+1
4688603:2 | R+1
4695244 | 131.04
4697239 | R+1
4751008 | R+1

# IfcSlab: Sol:Dalle BA - 25, Sol:Dalle BA - 25:4777275
In: R+1
Type - PredefinedType: FLOOR; Material: Béton - Béton coulé sur place 25 cm
Pset_QuantityTakeOff - Reference: Dalle BA - 25; sets with these values: 2
Pset_SlabCommon - LoadBearing: yes; IsExternal: no; Reference: Dalle BA - 25; PitchAngle: 35.5733 deg

# IfcSlab: Sol:PLATELAGE, Sol:PLATELAGE:4697608
In: R+1
Type - PredefinedType: FLOOR; Material: Bois - GL24c 3 cm
Pset_QuantityTakeOff - Reference: PLATELAGE; sets with these values: 2
Pset_SlabCommon - LoadBearing: yes; IsExternal: no; PitchAngle: 0 deg; Reference: PLATELAGE

# IfcSlab: Toit de base:Tôle 1000P (3)
Type - PredefinedType: ROOF
Material: tole 4 cm
Pset_QuantityTakeOff - Reference: Tôle 1000P; sets with these values: 2
Pset_SlabCommon - IsExternal: yes; Reference: Tôle 1000P
Name (Toit de base:Tôle 1000P:...) | In | PitchAngle (deg)
4842617 | faîtage | 41.9618
4865383 | R+3 | 35.5281
4963625 | R+1 | 34.9659

# IfcWall: Mur de base:BA - 20cm, Mur de base:BA - 20cm:4775746
In: RDC
Type - PredefinedType: STANDARD; Material: Béton - Béton coulé sur place 20 cm
Pset_QuantityTakeOff - Reference: BA - 20cm; sets with these values: 2
Pset_WallCommon - Reference: BA - 20cm; IsExternal: yes; ExtendToStructure: no; LoadBearing: yes

# IfcWall: Mur de base:BA - 22cm (20)
Type - PredefinedType: STANDARD; Material: Béton - Béton coulé sur place 22 cm
Pset_QuantityTakeOff - Reference: BA - 22cm; sets with these values: 2
Pset_WallCommon - IsExternal: yes; LoadBearing: yes; Reference: BA - 22cm
Name (Mur de base:BA - 22cm:...) | In | ExtendToStructure
4684037 | R+1 | yes
4684449 | R+1 | yes
4684611 | R+1 | yes
4685460 | R+1 | yes
4685759 | R+1 | yes
4686727 | R+1 | no
4696539 | RDC | yes
4697438 | RDC | yes
4697780 | RDC | no
4698824 | RDC | no
4698985 | RDC | yes
4701271 | R+1 | yes
4701281 | R+1 | yes
4762008 | RDC | no
4773215 | R+1 | no
4776080 | RDC | no
4800121 | RDC | yes
4963429 | 131.04 | no
4965228 | R+1 | yes
4968180 | R+1 | yes

# IfcWall: Mur de base:BA - 35 (3)
In: R+1
Type - PredefinedType: STANDARD; Material: Béton - Béton coulé sur place 35 cm
Pset_QuantityTakeOff - Reference: BA - 35; sets with these values: 2
Pset_WallCommon - IsExternal: yes; LoadBearing: yes; ExtendToStructure: yes; Reference: BA - 35
Name (Mur de base:BA - 35:...)
4684242
4684648
4686906

# IfcWall: Mur de base:cloison 11cm (3)
In: R+1
Type - PredefinedType: STANDARD; Material: Béton - Béton coulé sur place 11 cm
Pset_QuantityTakeOff - Reference: cloison 11cm; sets with these values: 2
Pset_WallCommon - IsExternal: yes; LoadBearing: yes; Reference: cloison 11cm
Name (Mur de base:cloison 11cm:...) | ExtendToStructure
4688166 | no
4688308 | no
5014156 | yes

# IfcWall: Murs 1:Murs 1, Murs 1:Murs 1:5028474
In: R+1
Type - Material: tole
Pset_QuantityTakeOff - Reference: Murs 1; sets with these values: 2
Pset_WallCommon - IsExternal: no; Reference: Murs 1

# IfcWall: Murs 2:Murs 1, Murs 2:Murs 1:4964930
In: R+1
Type - Material: tole
Pset_QuantityTakeOff - Reference: Murs 1; sets with these values: 2
Pset_WallCommon - IsExternal: no; Reference: Murs 1

# IfcWall: Murs 3:Murs 3, Murs 3:Murs 3:5033200
In: R+1
Type - Material: tole
Pset_QuantityTakeOff - Reference: Murs 3; sets with these values: 2
Pset_WallCommon - IsExternal: no; Reference: Murs 3

# IfcWallStandardCase: Mur de base:BA - 15cm (3)
Type - PredefinedType: STANDARD; Material: Béton - Béton coulé sur place 15 cm
Pset_QuantityTakeOff - Reference: BA - 15cm; sets with these values: 2
Pset_WallCommon - IsExternal: yes; ExtendToStructure: no; LoadBearing: yes; Reference: BA - 15cm
Name (Mur de base:BA - 15cm:...) | In
4681774 | RDC
4681826 | RDC
4687085 | R+1

# IfcWallStandardCase: Mur de base:BA - 18cm, Mur de base:BA - 18cm:4687341
In: R+1
Type - PredefinedType: STANDARD; Material: Béton - Béton coulé sur place 18 cm
Pset_QuantityTakeOff - Reference: BA - 18cm; sets with these values: 2
Pset_WallCommon - IsExternal: yes; ExtendToStructure: no; LoadBearing: yes; Reference: BA - 18cm

# IfcWallStandardCase: Mur de base:BA - 20cm (2)
Type - PredefinedType: STANDARD; Material: Béton - Béton coulé sur place 20 cm
Pset_QuantityTakeOff - Reference: BA - 20cm; sets with these values: 2
Pset_WallCommon - Reference: BA - 20cm; IsExternal: yes; ExtendToStructure: no; LoadBearing: yes
Name (Mur de base:BA - 20cm:...) | In
4676198 | 131.04
4676793 | RDC

# IfcWallStandardCase: Mur de base:BA - 22cm (46)
Type - PredefinedType: STANDARD; Material: Béton - Béton coulé sur place 22 cm
Pset_QuantityTakeOff - Reference: BA - 22cm; sets with these values: 2
Pset_WallCommon - IsExternal: yes; LoadBearing: yes; Reference: BA - 22cm
Name (Mur de base:BA - 22cm:...) | In | ExtendToStructure
4676512 | RDC | no
4676707 | RDC | no
4676869 | RDC | no
4677164 | 131.04 | no
4677622 | RDC | no
4678580 | RDC | no
4678810 | RDC | no
4679003 | RDC | no
4679463 | RDC | no
4679911 | RDC | no
4680275 | RDC | no
4680380 | RDC | no
4682051 | RDC | no
4682277 | RDC | no
4682518 | RDC | no
4682621 | RDC | no
4682738 | RDC | no
4684370 | R+1 | no
4684522 | R+1 | no
4684822 | R+1 | no
4685722 | R+1 | no
4686887 | R+1 | no
4687234 | R+1 | no
4696573 | RDC | no
4697045 | RDC | no
4697159 | RDC | no
4697291 | RDC | no
4698927 | RDC | no
4701843 | RDC | no
4751273 | 131.04 | no
4761429 | RDC | no
4765226 | R+1 | no
4770552 | RDC | yes
4770866 | RDC | no
4799169 | RDC | no
4799284 | RDC | no
4799346 | RDC | no
4799530 | RDC | no
4799609 | RDC | no
4800257 | R+1 | no
4940764 | RDC | yes
4940964 | RDC | no
4972053 | RDC | no
5012697 | R+1 | yes
5052657 | 131.04 | yes
5069506 | RDC | no

# IfcWallStandardCase: Mur de base:BA - 33cm (2)
In: RDC
Type - PredefinedType: STANDARD; Material: Béton - Béton coulé sur place 33 cm
Pset_QuantityTakeOff - Reference: BA - 33cm; sets with these values: 2
Pset_WallCommon - IsExternal: yes; ExtendToStructure: no; LoadBearing: yes; Reference: BA - 33cm
Name (Mur de base:BA - 33cm:...)
4677745
4679985

# IfcWallStandardCase: Mur de base:BA - 35 (2)
Type - PredefinedType: STANDARD; Material: Béton - Béton coulé sur place 35 cm
Pset_QuantityTakeOff - Reference: BA - 35; sets with these values: 2
Pset_WallCommon - IsExternal: yes; ExtendToStructure: no; LoadBearing: yes; Reference: BA - 35
Name (Mur de base:BA - 35:...) | In
4910110 | 131.04
4912690 | R+1

# IfcWallStandardCase: Mur de base:BA - 50cm 2, Mur de base:BA - 50cm 2:4685245
In: R+1
Type - PredefinedType: STANDARD; Material: Béton - Béton coulé sur place 50 cm
Pset_QuantityTakeOff - Reference: BA - 50cm 2; sets with these values: 2
Pset_WallCommon - IsExternal: yes; ExtendToStructure: no; LoadBearing: yes; Reference: BA - 50cm 2

# IfcWallStandardCase: Mur de base:cloison 11cm (20)
Type - PredefinedType: STANDARD; Material: Béton - Béton coulé sur place 11 cm
Pset_QuantityTakeOff - Reference: cloison 11cm; sets with these values: 2
Pset_WallCommon - IsExternal: yes; LoadBearing: yes; Reference: cloison 11cm
Name (Mur de base:cloison 11cm:...) | In | ExtendToStructure
4679135 | RDC | no
4679550 | RDC | no
4679642 | RDC | no
4679713 | RDC | no
4680638 | RDC | no
4680720 | RDC | no
4680942 | RDC | no
4681050 | RDC | no
4681436 | RDC | no
4681673 | RDC | no
4682891 | RDC | no
4683054 | RDC | no
4683156 | RDC | no
4683223 | RDC | no
4687512 | R+1 | no
4687580 | R+1 | no
4687800 | R+1 | yes
4687962 | R+1 | no
4688067 | R+1 | yes
4688225 | R+1 | no
